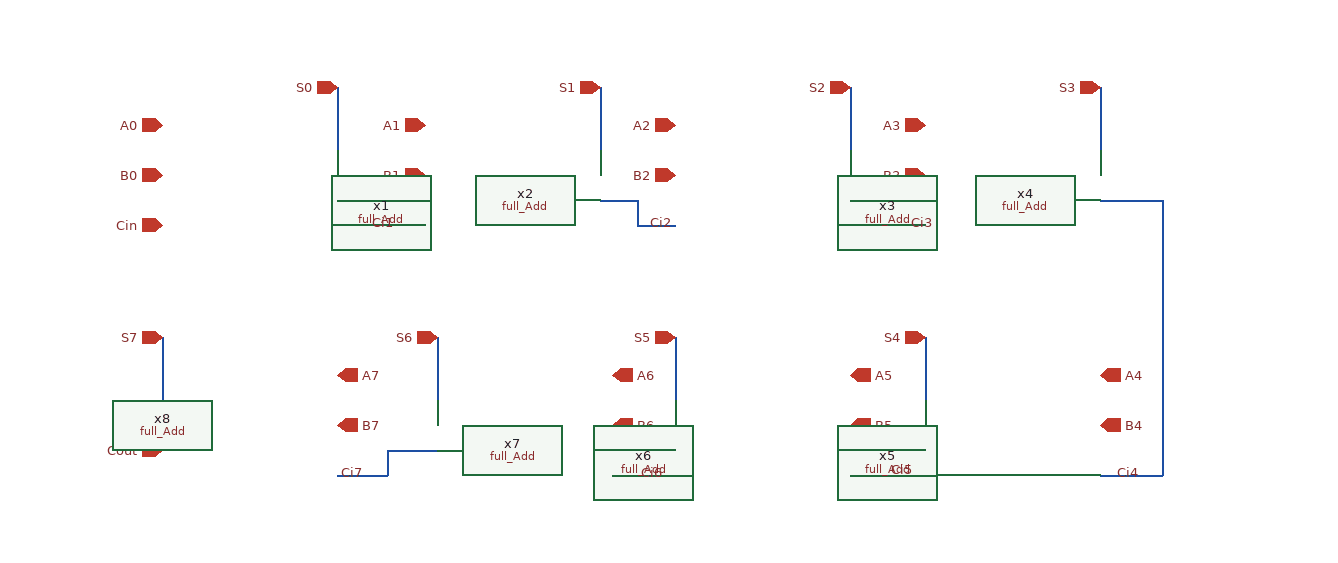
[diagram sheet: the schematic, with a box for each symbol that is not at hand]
v {xschem version=3.4.8RC file_version=1.3}
G {}
K {}
V {}
S {}
F {}
E {}
N 210 -380 230 -380 {lab=Ci1}
N 230 -380 230 -360 {lab=Ci1}
N 430 -380 450 -380 {lab=Ci2}
N 450 -380 450 -360 {lab=Ci2}
N 450 -360 480 -360 {lab=Ci2}
N 620 -380 660 -380 {lab=Ci3}
N 660 -380 660 -360 {lab=Ci3}
N 660 -360 680 -360 {lab=Ci3}
N 650 -180 680 -180 {lab=Ci5}
N 650 -180 650 -160 {lab=Ci5}
N 620 -160 650 -160 {lab=Ci5}
N 450 -180 480 -180 {lab=Ci6}
N 450 -180 450 -160 {lab=Ci6}
N 430 -160 450 -160 {lab=Ci6}
N 250 -180 290 -180 {lab=Ci7}
N 250 -180 250 -160 {lab=Ci7}
N 210 -160 250 -160 {lab=Ci7}
N 820 -380 860 -380 {lab=Ci4}
N 860 -380 870 -380 {lab=Ci4}
N 870 -380 870 -160 {lab=Ci4}
N 820 -160 870 -160 {lab=Ci4}
N 230 -360 280 -360 {lab=Ci1}
N 420 -380 430 -380 {lab=Ci2}
N 210 -470 210 -420 {lab=S0}
N 420 -470 420 -420 {lab=S1}
N 620 -470 620 -420 {lab=S2}
N 820 -470 820 -420 {lab=S3}
N 70 -270 70 -220 {lab=S7}
N 290 -270 290 -220 {lab=S6}
N 480 -270 480 -220 {lab=S5}
N 680 -270 680 -220 {lab=S4}
C {title.sym} 160 -50 0 0 {name=l5 author="Stefan Schippers"}
C {ipin.sym} 70 -440 0 0 {name=p1 lab=A0}
C {ipin.sym} 70 -400 0 0 {name=p2 lab=B0}
C {ipin.sym} 280 -440 0 0 {name=p3 lab=A1}
C {ipin.sym} 280 -400 0 0 {name=p5 lab=B1
}
C {ipin.sym} 480 -440 0 0 {name=p6 lab=A2}
C {ipin.sym} 480 -400 0 0 {name=p9 lab=B2}
C {ipin.sym} 680 -440 0 0 {name=p10 lab=A3}
C {ipin.sym} 680 -400 0 0 {name=p11 lab=B3}
C {ipin.sym} 820 -240 0 1 {name=p12 lab=A4}
C {ipin.sym} 820 -200 0 1 {name=p13 lab=B4}
C {ipin.sym} 620 -240 0 1 {name=p14 lab=A5}
C {ipin.sym} 620 -200 0 1 {name=p15 lab=B5}
C {ipin.sym} 430 -240 0 1 {name=p16 lab=A6}
C {ipin.sym} 430 -200 0 1 {name=p17 lab=B6}
C {ipin.sym} 210 -240 0 1 {name=p18 lab=A7}
C {ipin.sym} 210 -200 0 1 {name=p19 lab=B7}
C {opin.sym} 210 -470 1 1 {name=p20 lab=S0}
C {opin.sym} 420 -470 1 1 {name=p21 lab=S1}
C {opin.sym} 620 -470 1 1 {name=p22 lab=S2}
C {opin.sym} 820 -470 1 1 {name=p23 lab=S3}
C {opin.sym} 70 -270 1 1 {name=p24 lab=S7}
C {opin.sym} 290 -270 1 1 {name=p25 lab=S6}
C {opin.sym} 480 -270 1 1 {name=p26 lab=S5}
C {opin.sym} 680 -270 1 1 {name=p27 lab=S4}
C {opin.sym} 70 -180 0 1 {name=p28 lab=Cout}
C {/home/suraj/projects/CMOS/HALF_ADDER/layout/full_add/schematic/full_Add.sym} 250 -400 0 0 {name=x1}
C {/home/suraj/projects/CMOS/HALF_ADDER/layout/full_add/schematic/full_Add.sym} 460 -400 0 0 {name=x2}
C {/home/suraj/projects/CMOS/HALF_ADDER/layout/full_add/schematic/full_Add.sym} 660 -400 0 0 {name=x3}
C {/home/suraj/projects/CMOS/HALF_ADDER/layout/full_add/schematic/full_Add.sym} 860 -400 0 0 {name=x4}
C {/home/suraj/projects/CMOS/HALF_ADDER/layout/full_add/schematic/full_Add.sym} 640 -200 0 1 {name=x5}
C {/home/suraj/projects/CMOS/HALF_ADDER/layout/full_add/schematic/full_Add.sym} 440 -200 0 1 {name=x6}
C {/home/suraj/projects/CMOS/HALF_ADDER/layout/full_add/schematic/full_Add.sym} 250 -200 0 1 {name=x7}
C {/home/suraj/projects/CMOS/HALF_ADDER/layout/full_add/schematic/full_Add.sym} 30 -200 0 1 {name=x8}
C {lab_wire.sym} 257.5 -360 0 0 {name=p4 sig_type=std_logic lab=Ci1}
C {lab_wire.sym} 480 -360 0 0 {name=p7 sig_type=std_logic lab=Ci2}
C {lab_wire.sym} 666.25 -360 0 1 {name=p8 sig_type=std_logic lab=Ci3}
C {lab_wire.sym} 831.25 -160 0 1 {name=p29 sig_type=std_logic lab=Ci4}
C {lab_wire.sym} 650 -162.5 0 1 {name=p30 sig_type=std_logic lab=Ci5}
C {lab_wire.sym} 450 -160 0 1 {name=p31 sig_type=std_logic lab=Ci6}
C {lab_wire.sym} 210 -160 0 1 {name=p32 sig_type=std_logic lab=Ci7}
C {ipin.sym} 70 -360 0 0 {name=p33 lab=Cin}
